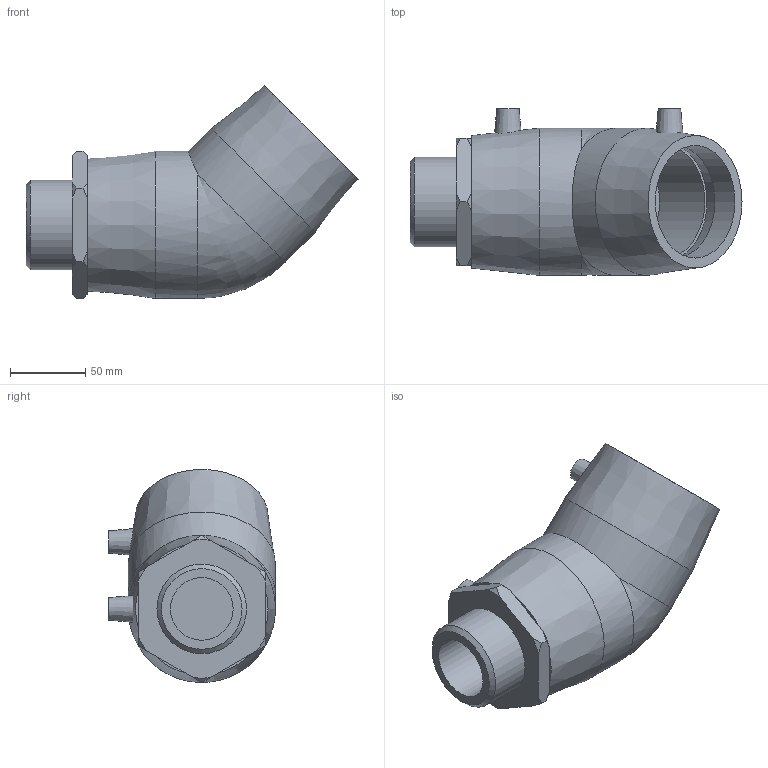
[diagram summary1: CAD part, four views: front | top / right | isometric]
STEP (ISO 10303-21) file: header records copied from the file, then geometry measured from it (millimetres).
FILE_DESCRIPTION(/* description */ ('PLASSON 45° ELBOW TRANSITION MALE 75-2"'),/* implementation_level */ '2;1');
FILE_NAME(/* name */ 'C:\Dropbox\KIMPROJECTS-Inventor\99-16-3568-Processing\ElectroFusion Fittings\02.02.20\492604\492604075020.ipt.stp',/* time_stamp */ '2020-02-02T12:20:11+02:00',/* author */ ('KIM'),/* organization */ (''),/* preprocessor_version */ 'ST-DEVELOPER v15.6',/* originating_system */ 'Autodesk Inventor 2015',/* authorisation */ '');
FILE_SCHEMA (('AUTOMOTIVE_DESIGN { 1 0 10303 214 3 1 1 }'));
Length unit declared in the file: millimetre
Products named in the file (1): 492604075020
Bounding box: 221 x 111 x 141.83 mm (x, y, z)
Volume: 811423.9 mm3; surface area: 123301.4 mm2
Topology: 1 solids, 2 shells, 59 faces, 133 edges, 88 vertices
Faces by surface type: plane 24, cone 19, cylinder 15, bspline 1
Full cylindrical faces by diameter (mm): 4 x2, 10 x2, 41.73 x1, 48.75 x2, 59 x1, 59.614 x1, 75 x4, 98 x2
Entity records: 1494 total; most frequent: CARTESIAN_POINT 363, DIRECTION 236, ORIENTED_EDGE 188, AXIS2_PLACEMENT_3D 109, EDGE_LOOP 97, EDGE_CURVE 94, VERTEX_POINT 75, FACE_OUTER_BOUND 59
One B-rep face of a CAD part: STEP entity #746.
In plain terms, the planar face has unit normal (-1, 0, 0).
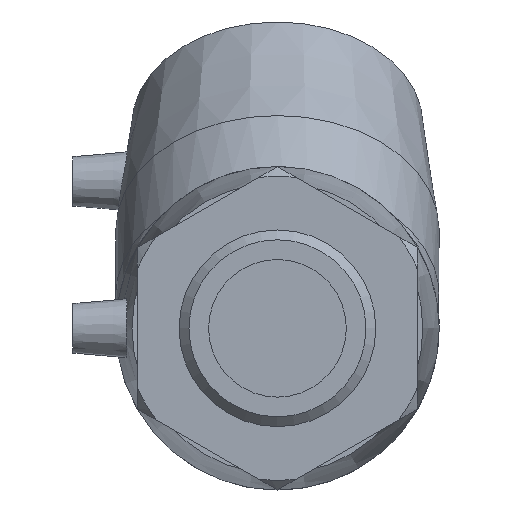
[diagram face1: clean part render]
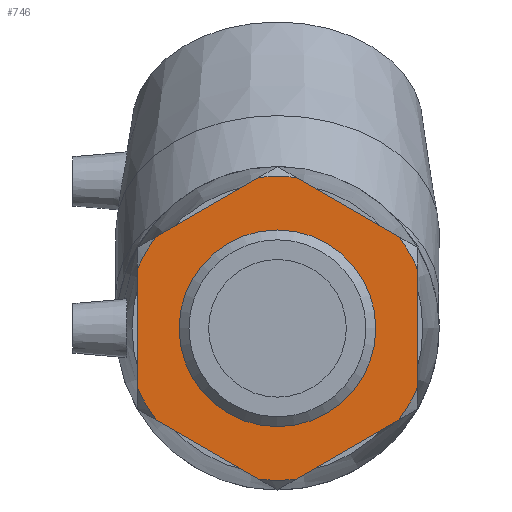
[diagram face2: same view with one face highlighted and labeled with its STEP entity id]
Its self-contained STEP definition (entity closure, numbers rounded to 3 decimals):
#19=LINE('',#1163,#37);
#23=LINE('',#1187,#41);
#26=LINE('',#1209,#44);
#29=LINE('',#1231,#47);
#34=LINE('',#1268,#52);
#36=LINE('',#1287,#54);
#37=VECTOR('',#926,35.82);
#41=VECTOR('',#932,35.82);
#44=VECTOR('',#937,35.82);
#47=VECTOR('',#942,35.82);
#52=VECTOR('',#949,35.82);
#54=VECTOR('',#953,35.82);
#101=PLANE('',#813);
#121=FACE_BOUND('',#228,.T.);
#165=FACE_OUTER_BOUND('',#227,.T.);
#227=EDGE_LOOP('',(#584,#585,#586,#587,#588,#589,#590,#591,#592,#593,#594,
#595));
#228=EDGE_LOOP('',(#596));
#315=CIRCLE('',#806,29.807);
#316=CIRCLE('',#814,46.06);
#317=CIRCLE('',#815,46.06);
#318=CIRCLE('',#816,46.06);
#319=CIRCLE('',#817,46.06);
#320=CIRCLE('',#818,46.06);
#321=CIRCLE('',#819,46.06);
#364=VERTEX_POINT('',#1154);
#365=VERTEX_POINT('',#1157);
#367=VERTEX_POINT('',#1162);
#373=VERTEX_POINT('',#1182);
#374=VERTEX_POINT('',#1186);
#379=VERTEX_POINT('',#1204);
#380=VERTEX_POINT('',#1208);
#385=VERTEX_POINT('',#1226);
#386=VERTEX_POINT('',#1230);
#392=VERTEX_POINT('',#1249);
#396=VERTEX_POINT('',#1264);
#397=VERTEX_POINT('',#1270);
#400=VERTEX_POINT('',#1283);
#439=EDGE_CURVE('',#364,#364,#315,.T.);
#441=EDGE_CURVE('',#367,#365,#19,.T.);
#449=EDGE_CURVE('',#374,#373,#23,.T.);
#456=EDGE_CURVE('',#380,#379,#26,.T.);
#463=EDGE_CURVE('',#386,#385,#29,.T.);
#475=EDGE_CURVE('',#392,#396,#34,.T.);
#481=EDGE_CURVE('',#397,#400,#36,.T.);
#482=EDGE_CURVE('',#392,#400,#316,.T.);
#483=EDGE_CURVE('',#386,#396,#317,.T.);
#484=EDGE_CURVE('',#380,#385,#318,.T.);
#485=EDGE_CURVE('',#374,#379,#319,.T.);
#486=EDGE_CURVE('',#367,#373,#320,.T.);
#487=EDGE_CURVE('',#397,#365,#321,.T.);
#584=ORIENTED_EDGE('',*,*,#481,.T.);
#585=ORIENTED_EDGE('',*,*,#482,.F.);
#586=ORIENTED_EDGE('',*,*,#475,.T.);
#587=ORIENTED_EDGE('',*,*,#483,.F.);
#588=ORIENTED_EDGE('',*,*,#463,.T.);
#589=ORIENTED_EDGE('',*,*,#484,.F.);
#590=ORIENTED_EDGE('',*,*,#456,.T.);
#591=ORIENTED_EDGE('',*,*,#485,.F.);
#592=ORIENTED_EDGE('',*,*,#449,.T.);
#593=ORIENTED_EDGE('',*,*,#486,.F.);
#594=ORIENTED_EDGE('',*,*,#441,.T.);
#595=ORIENTED_EDGE('',*,*,#487,.F.);
#596=ORIENTED_EDGE('',*,*,#439,.T.);
#746=ADVANCED_FACE('',(#165,#121),#101,.T.);
#806=AXIS2_PLACEMENT_3D('',#1155,#922,#923);
#813=AXIS2_PLACEMENT_3D('',#1288,#954,#955);
#814=AXIS2_PLACEMENT_3D('',#1289,#956,#957);
#815=AXIS2_PLACEMENT_3D('',#1290,#958,#959);
#816=AXIS2_PLACEMENT_3D('',#1291,#960,#961);
#817=AXIS2_PLACEMENT_3D('',#1292,#962,#963);
#818=AXIS2_PLACEMENT_3D('',#1293,#964,#965);
#819=AXIS2_PLACEMENT_3D('',#1294,#966,#967);
#922=DIRECTION('center_axis',(1.,0.,0.));
#923=DIRECTION('ref_axis',(0.,0.,-1.));
#926=DIRECTION('',(0.,0.,-1.));
#932=DIRECTION('',(0.,0.866,-0.5));
#937=DIRECTION('',(0.,0.866,0.5));
#942=DIRECTION('',(0.,0.,1.));
#949=DIRECTION('',(0.,-0.866,0.5));
#953=DIRECTION('',(0.,-0.866,-0.5));
#954=DIRECTION('center_axis',(-1.,0.,0.));
#955=DIRECTION('ref_axis',(0.,0.,1.));
#956=DIRECTION('center_axis',(1.,0.,0.));
#957=DIRECTION('ref_axis',(0.,0.,1.));
#958=DIRECTION('center_axis',(1.,0.,0.));
#959=DIRECTION('ref_axis',(0.,0.,1.));
#960=DIRECTION('center_axis',(1.,0.,0.));
#961=DIRECTION('ref_axis',(0.,0.,1.));
#962=DIRECTION('center_axis',(1.,0.,0.));
#963=DIRECTION('ref_axis',(0.,0.,1.));
#964=DIRECTION('center_axis',(1.,0.,0.));
#965=DIRECTION('ref_axis',(0.,0.,1.));
#966=DIRECTION('center_axis',(1.,0.,0.));
#967=DIRECTION('ref_axis',(0.,0.,1.));
#1154=CARTESIAN_POINT('',(-97.525,0.,-29.807));
#1155=CARTESIAN_POINT('Origin',(-97.525,0.,0.));
#1157=CARTESIAN_POINT('',(-97.525,42.435,-17.91));
#1162=CARTESIAN_POINT('',(-97.525,42.435,17.91));
#1163=CARTESIAN_POINT('',(-97.525,42.435,-36.75));
#1182=CARTESIAN_POINT('',(-97.525,36.728,27.795));
#1186=CARTESIAN_POINT('',(-97.525,5.707,45.705));
#1187=CARTESIAN_POINT('',(-97.525,42.435,24.5));
#1204=CARTESIAN_POINT('',(-97.525,-5.707,45.705));
#1208=CARTESIAN_POINT('',(-97.525,-36.728,27.795));
#1209=CARTESIAN_POINT('',(-97.525,-21.218,36.75));
#1226=CARTESIAN_POINT('',(-97.525,-42.435,17.91));
#1230=CARTESIAN_POINT('',(-97.525,-42.435,-17.91));
#1231=CARTESIAN_POINT('',(-97.525,-42.435,-12.25));
#1249=CARTESIAN_POINT('',(-97.525,-5.707,-45.705));
#1264=CARTESIAN_POINT('',(-97.525,-36.728,-27.795));
#1268=CARTESIAN_POINT('',(-97.525,-21.218,-36.75));
#1270=CARTESIAN_POINT('',(-97.525,36.728,-27.795));
#1283=CARTESIAN_POINT('',(-97.525,5.707,-45.705));
#1287=CARTESIAN_POINT('',(-97.525,0.,-49.));
#1288=CARTESIAN_POINT('Origin',(-97.525,0.,-49.));
#1289=CARTESIAN_POINT('Origin',(-97.525,0.,0.));
#1290=CARTESIAN_POINT('Origin',(-97.525,0.,0.));
#1291=CARTESIAN_POINT('Origin',(-97.525,0.,0.));
#1292=CARTESIAN_POINT('Origin',(-97.525,0.,0.));
#1293=CARTESIAN_POINT('Origin',(-97.525,0.,0.));
#1294=CARTESIAN_POINT('Origin',(-97.525,0.,0.));
